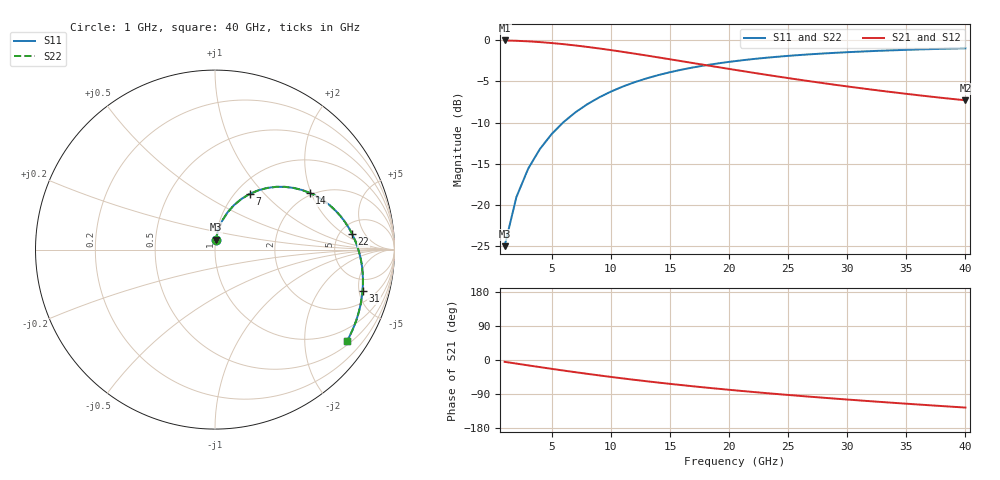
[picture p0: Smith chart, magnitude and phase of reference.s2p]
! circuitRF F0 spike reference -- case A, openEMS, thin PEC curve on grid edges, dw 25 um
! openEMS probes -> S by postproc.py (own time column per probe); port 1 excited only;
! S22 = S11 and S12 = S21 by the mirror symmetry of the geometry (not a second run)
# GHz S RI R 50
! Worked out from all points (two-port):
!   40 points, 1 GHz to 40 GHz, reference 50 ohm
!   highest |S21| = -0.01 dB at 1 GHz (marker M1); lowest = -7.3 dB at 40 GHz (marker M2)
!   |S21| within 3 dB of the highest: start of sweep to 18.03 GHz
!   lowest |S11| = -25.0 dB at 1 GHz (marker M3), VSWR 1.12, Z = 50.1 + j5.63 ohm
!   |S11| at or under -10 dB: start of sweep to 5.945 GHz
!   |S22| runs from -25.0 to -1.0 dB; largest |S21 - S12| = 0
!   S11 on the Smith chart (normalised r, x): 1 GHz: 1.00, +0.11; 7 GHz: 1.16, +0.83; 14 GHz: 1.92, +1.95; 22 GHz: 6.47, +2.76; 31 GHz: 3.19, -5.43; 40 GHz: 0.61, -3.10
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1  0.00461 0.0559  0.995 -0.0829  0.995 -0.0829  0.00461 0.0559
2  0.0183 0.1102  0.9801 -0.164  0.9801 -0.164  0.0183 0.1102
3  0.0404 0.1613  0.956 -0.2419  0.956 -0.2419  0.0404 0.1613
4  0.0702 0.2077  0.9234 -0.315  0.9234 -0.315  0.0702 0.2077
5  0.1065 0.2485  0.8835 -0.3823  0.8835 -0.3823  0.1065 0.2485
6  0.148 0.2828  0.8377 -0.4429  0.8377 -0.4429  0.148 0.2828
7  0.1934 0.3101  0.7873 -0.4964  0.7873 -0.4964  0.1934 0.3101
8  0.2415 0.3303  0.7334 -0.5425  0.7334 -0.5425  0.2415 0.3303
9  0.2909 0.3434  0.6775 -0.5813  0.6775 -0.5813  0.2909 0.3434
11  0.3899 0.3496  0.5636 -0.6382  0.5636 -0.6382  0.3899 0.3496
12  0.4377 0.3437  0.5074 -0.6572  0.5074 -0.6572  0.4377 0.3437
14  0.5269 0.3166  0.3995 -0.6791  0.3995 -0.6791  0.5269 0.3166
17  0.6394 0.2469  0.2544 -0.6808  0.2544 -0.6808  0.6394 0.2469
19  0.6986 0.1874  0.1704 -0.6672  0.1704 -0.6672  0.6986 0.1874
21  0.7454 0.1215  0.0968 -0.6458  0.0968 -0.6458  0.7454 0.1215
22  0.7643 0.087  0.0636 -0.633  0.0636 -0.633  0.7643 0.087
24  0.7936 0.0163  0.00391 -0.6045  0.00391 -0.6045  0.7936 0.0163
27  0.8187 -0.0911  -0.0705 -0.5575  -0.0705 -0.5575  0.8187 -0.0911
31  0.8219 -0.2309  -0.1466 -0.4921  -0.1466 -0.4921  0.8219 -0.2309
34  0.8057 -0.33  -0.19 -0.4435  -0.19 -0.4435  0.8057 -0.33
37  0.7765 -0.4228  -0.2242 -0.3966  -0.2242 -0.3966  0.7765 -0.4228
40  0.7363 -0.5084  -0.2511 -0.3518  -0.2511 -0.3518  0.7363 -0.5084
